
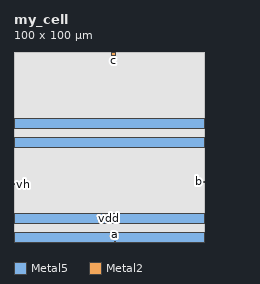
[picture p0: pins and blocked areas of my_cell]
MACRO my_cell
    CLASS BLOCK ;
    ORIGIN 0.000 0.000 ;
    FOREIGN my_cell 0.000 0.000 ;
    SIZE 100.000 BY 100.000 ;
    SYMMETRY X Y R90 ;
  PIN vss
    DIRECTION INOUT ;
    USE GROUND ;
    PORT
      LAYER Metal5 ;
        RECT 0.000 0.000 100.000 5.000 ;
    END
    PORT
      LAYER Metal5 ;
        RECT 0.000 50.000 100.000 55.000 ;
    END
  END vss
  PIN vdd 
    DIRECTION INOUT ;
    USE POWER ;
    PORT
      LAYER Metal5 ;
        RECT 0.000 10.000 100.000 15.000 ;
    END
    PORT
      LAYER Metal5 ;
        RECT 0.000 60.000 100.000 65.000 ;
    END
  END vdd
  PIN a 
    DIRECTION INPUT ;
    USE SIGNAL ;
    PORT
      LAYER Metal2 ;
        RECT 53.100 0.000 53.500 0.400 ;
    END
  END a
  PIN b 
    DIRECTION INPUT ;
    USE SIGNAL ;
    PORT
      LAYER Metal2 ;
        RECT 99.600 31.400 100.000 31.800 ;
    END
  END b
  PIN c 
    DIRECTION OUTPUT ;
    USE SIGNAL ;
    PORT
      LAYER Metal2 ;
        RECT 51.500 98.000 53.500 100.000 ;
    END
  END c
  PIN vh 
    DIRECTION INOUT ;
    USE SIGNAL ;
    PORT
      LAYER Metal2 ;
        RECT 0.000 30.300 0.400 30.700 ;
    END
  END vh
  OBS
    LAYER Metal1 ;
      RECT 0.000 0.000 100.000 100.000 ;
    LAYER Metal2 ;
      RECT 0.000 0.000 100.000 100.000 ;
    LAYER Metal3 ;
      RECT 0.000 0.000 100.000 100.000 ;
    LAYER Metal4 ;
      RECT 0.000 0.000 100.000 100.000 ;
    LAYER Metal5 ;
      RECT 0.000 0.000 100.000 100.000 ;
    LAYER Via1 ;
      RECT 0.000 0.000 100.000 100.000 ;
    LAYER Via2 ;
      RECT 0.000 0.000 100.000 100.000 ;
  END
END my_cell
